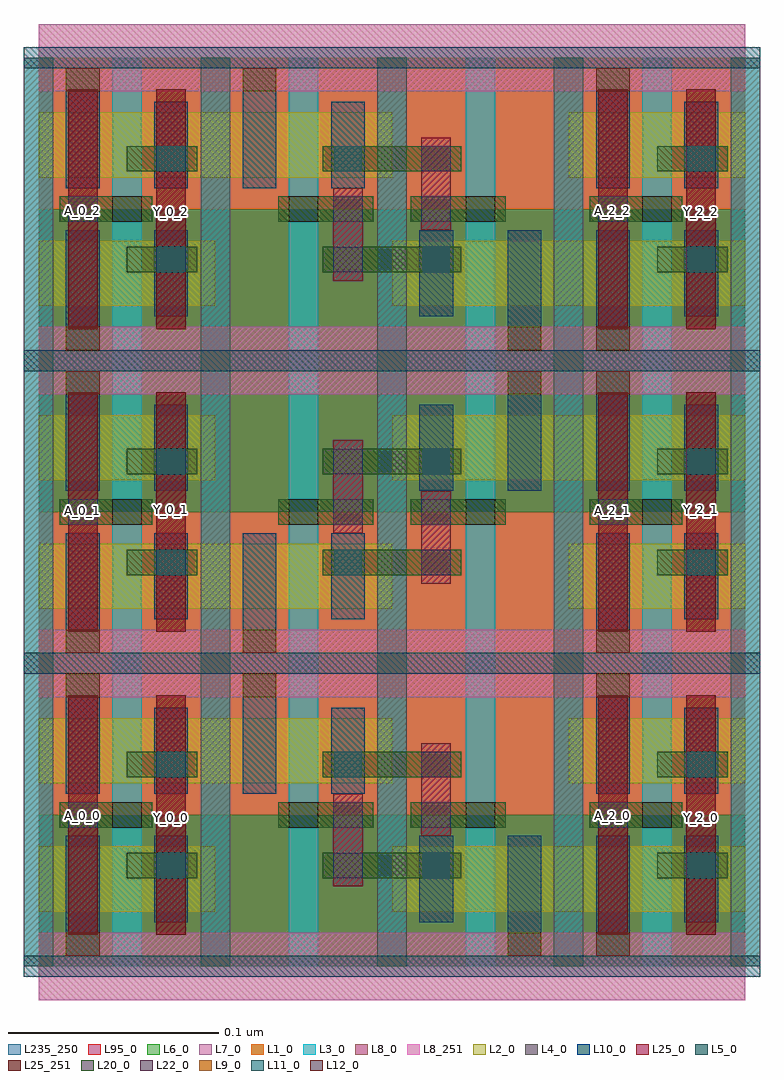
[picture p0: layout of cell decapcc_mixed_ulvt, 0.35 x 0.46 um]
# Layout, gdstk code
from math import pi, radians
import gdstk
lib = gdstk.Library(unit=1e-6, precision=5e-10)
def R(c, l, rs):  # rectangles x0, y0, x1, y1
    for r in rs: c.add(gdstk.rectangle(r[:2], r[2:], *l))
def A(c, l, x, y, w, h, nx, ny, dx, dy):  # array of equal rectangles
    R(c, l, [(x+i*dx, y+j*dy, x+i*dx+w, y+j*dy+h) for i in range(nx) for j in range(ny)])
L1_0 = (1, 0)
L2_0 = (2, 0)
L3_0 = (3, 0)
L4_0 = (4, 0)
L5_0 = (5, 0)
L6_0 = (6, 0)
L7_0 = (7, 0)
L8_0 = (8, 0)
L8_251 = (8, 251)
L9_0 = (9, 0)
L10_0 = (10, 0)
L11_0 = (11, 0)
L12_0 = (12, 0)
L20_0 = (20, 0)
L22_0 = (22, 0)
L25_0 = (25, 0)
L25_251 = (25, 251)
L95_0 = (95, 0)
L235_250 = (235, 250)

gt2_6t_inv_x1_w31_ulvt = lib.new_cell('gt2_6t_inv_x1_w31_ulvt')
R(gt2_6t_inv_x1_w31_ulvt, L1_0, [(0,0.072,0.084,0.144)])
R(gt2_6t_inv_x1_w31_ulvt, L2_0, [(0,0.026,0.084,0.057), (0,0.087,0.084,0.118)])
A(gt2_6t_inv_x1_w31_ulvt, L3_0, -0.007, 0, 0.014, 0.144, 3, 1, 0.042, 0)
R(gt2_6t_inv_x1_w31_ulvt, L4_0, [(-0.007,0,0.007,0.144), (0.077,0,0.091,0.144)])
R(gt2_6t_inv_x1_w31_ulvt, L5_0, [(-0.007,-0.005,0.091,0.005), (-0.007,0.139,0.091,0.149)])
R(gt2_6t_inv_x1_w31_ulvt, L6_0, [(0,0,0.084,0.072)])
R(gt2_6t_inv_x1_w31_ulvt, L7_0, [(0,0.072,0.084,0.144)])
R(gt2_6t_inv_x1_w31_ulvt, L8_0, [(0,-0.016,0.084,0.016), (0,0.128,0.084,0.16)])
R(gt2_6t_inv_x1_w31_ulvt, L8_251, [(0,-0.016,0.084,0.016), (0,0.128,0.084,0.16)])
R(gt2_6t_inv_x1_w31_ulvt, L9_0, [(0.013,0.005,0.029,0.016), (0.013,0.128,0.029,0.139)])
R(gt2_6t_inv_x1_w31_ulvt, L10_0, [(0.013,0.005,0.029,0.062), (0.055,0.021,0.071,0.062), (0.013,0.082,0.029,0.139), (0.055,0.082,0.071,0.123)])
R(gt2_6t_inv_x1_w31_ulvt, L11_0, [(0.0565,0.042,0.0695,0.054), (0.0565,0.09,0.0695,0.102)])
R(gt2_6t_inv_x1_w31_ulvt, L12_0, [(0.035,0.066,0.049,0.078)])
R(gt2_6t_inv_x1_w31_ulvt, L20_0, [(0.042,0.042,0.0755,0.054), (0.01,0.066,0.054,0.078), (0.042,0.09,0.0755,0.102)])
R(gt2_6t_inv_x1_w31_ulvt, L22_0, [(0.056,0.042,0.07,0.054), (0.014,0.066,0.028,0.078), (0.056,0.09,0.07,0.102)])
R(gt2_6t_inv_x1_w31_ulvt, L25_0, [(0.014,0.015,0.028,0.129), (0.056,0.015,0.07,0.129)])
R(gt2_6t_inv_x1_w31_ulvt, L25_251, [(0.014,0.015,0.028,0.129), (0.056,0.015,0.07,0.129)])
R(gt2_6t_inv_x1_w31_ulvt, L95_0, [(0,0,0.084,0.144)])
R(gt2_6t_inv_x1_w31_ulvt, L235_250, [(0,0,0.084,0.144)])
gt2_6t_inv_x1_w31_ulvt.add(gdstk.Label('vdd', (0.022,0.144), layer=8, texttype=251))
gt2_6t_inv_x1_w31_ulvt.add(gdstk.Label('vss', (0.042,0.0035), layer=8, texttype=251))
gt2_6t_inv_x1_w31_ulvt.add(gdstk.Label('A', (0.021,0.0715), layer=25, texttype=251))
gt2_6t_inv_x1_w31_ulvt.add(gdstk.Label('Y', (0.063,0.071), layer=25, texttype=251))

gt2_6t_decapcc_cp_w31_ul = lib.new_cell('gt2_6t_decapcc_cp_w31_ulvt')
R(gt2_6t_decapcc_cp_w31_ul, L1_0, [(0,0.072,0.168,0.144)])
R(gt2_6t_decapcc_cp_w31_ul, L2_0, [(0,0.026,0.084,0.057), (0.084,0.087,0.168,0.118)])
A(gt2_6t_decapcc_cp_w31_ul, L3_0, -0.007, 0, 0.014, 0.144, 5, 1, 0.042, 0)
A(gt2_6t_decapcc_cp_w31_ul, L4_0, -0.007, 0, 0.014, 0.144, 3, 1, 0.084, 0)
R(gt2_6t_decapcc_cp_w31_ul, L5_0, [(-0.007,-0.005,0.175,0.005), (-0.007,0.139,0.175,0.149)])
R(gt2_6t_decapcc_cp_w31_ul, L6_0, [(0,0,0.168,0.072)])
R(gt2_6t_decapcc_cp_w31_ul, L7_0, [(0,0.072,0.168,0.144)])
R(gt2_6t_decapcc_cp_w31_ul, L8_0, [(0,-0.016,0.168,0.016), (0,0.128,0.168,0.16)])
R(gt2_6t_decapcc_cp_w31_ul, L8_251, [(0,-0.016,0.168,0.016), (0,0.128,0.168,0.16)])
R(gt2_6t_decapcc_cp_w31_ul, L9_0, [(0.013,0.005,0.029,0.016), (0.139,0.128,0.155,0.139)])
R(gt2_6t_decapcc_cp_w31_ul, L10_0, [(0.013,0.005,0.029,0.062), (0.055,0.021,0.071,0.062), (0.097,0.082,0.113,0.123), (0.139,0.082,0.155,0.139)])
R(gt2_6t_decapcc_cp_w31_ul, L11_0, [(0.0565,0.042,0.0695,0.054), (0.0985,0.09,0.1115,0.102)])
R(gt2_6t_decapcc_cp_w31_ul, L12_0, [(0.035,0.066,0.049,0.078), (0.119,0.066,0.133,0.078)])
R(gt2_6t_decapcc_cp_w31_ul, L20_0, [(0.051,0.042,0.117,0.054), (0.03,0.066,0.075,0.078), (0.093,0.066,0.138,0.078), (0.051,0.09,0.117,0.102)])
R(gt2_6t_decapcc_cp_w31_ul, L22_0, [(0.098,0.042,0.112,0.054), (0.056,0.066,0.07,0.078), (0.098,0.066,0.112,0.078), (0.056,0.09,0.07,0.102)])
R(gt2_6t_decapcc_cp_w31_ul, L25_0, [(0.098,0.038,0.112,0.082), (0.056,0.062,0.07,0.106)])
R(gt2_6t_decapcc_cp_w31_ul, L95_0, [(0,0,0.168,0.144)])
R(gt2_6t_decapcc_cp_w31_ul, L235_250, [(0,0,0.168,0.144)])
gt2_6t_decapcc_cp_w31_ul.add(gdstk.Label('vss', (0.084,0), layer=8, texttype=251))
gt2_6t_decapcc_cp_w31_ul.add(gdstk.Label('vdd', (0.084,0.144), layer=8, texttype=251))

decapcc_mixed_ulvt = lib.new_cell('decapcc_mixed_ulvt')
decapcc_mixed_ulvt.add(gdstk.Reference(gt2_6t_inv_x1_w31_ulvt, (0,0)))
decapcc_mixed_ulvt.add(gdstk.Reference(gt2_6t_decapcc_cp_w31_ul, (0.252,0), rotation=pi, x_reflection=True))
decapcc_mixed_ulvt.add(gdstk.Reference(gt2_6t_inv_x1_w31_ulvt, (0.252,0)))
decapcc_mixed_ulvt.add(gdstk.Reference(gt2_6t_inv_x1_w31_ulvt, (0,0.288), x_reflection=True))
decapcc_mixed_ulvt.add(gdstk.Reference(gt2_6t_decapcc_cp_w31_ul, (0.252,0.288), rotation=pi))
decapcc_mixed_ulvt.add(gdstk.Reference(gt2_6t_inv_x1_w31_ulvt, (0.252,0.288), x_reflection=True))
decapcc_mixed_ulvt.add(gdstk.Reference(gt2_6t_inv_x1_w31_ulvt, (0,0.288)))
decapcc_mixed_ulvt.add(gdstk.Reference(gt2_6t_decapcc_cp_w31_ul, (0.252,0.288), rotation=pi, x_reflection=True))
decapcc_mixed_ulvt.add(gdstk.Reference(gt2_6t_inv_x1_w31_ulvt, (0.252,0.288)))
decapcc_mixed_ulvt.add(gdstk.Label('A_0_0', (0.021,0.0715), layer=25, texttype=251))
decapcc_mixed_ulvt.add(gdstk.Label('Y_0_0', (0.063,0.071), layer=25, texttype=251))
decapcc_mixed_ulvt.add(gdstk.Label('A_2_0', (0.273,0.0715), layer=25, texttype=251))
decapcc_mixed_ulvt.add(gdstk.Label('Y_2_0', (0.315,0.071), layer=25, texttype=251))
decapcc_mixed_ulvt.add(gdstk.Label('A_0_1', (0.021,0.2165), layer=25, texttype=251))
decapcc_mixed_ulvt.add(gdstk.Label('Y_0_1', (0.063,0.217), layer=25, texttype=251))
decapcc_mixed_ulvt.add(gdstk.Label('A_2_1', (0.273,0.2165), layer=25, texttype=251))
decapcc_mixed_ulvt.add(gdstk.Label('Y_2_1', (0.315,0.217), layer=25, texttype=251))
decapcc_mixed_ulvt.add(gdstk.Label('A_0_2', (0.021,0.3595), layer=25, texttype=251))
decapcc_mixed_ulvt.add(gdstk.Label('Y_0_2', (0.063,0.359), layer=25, texttype=251))
decapcc_mixed_ulvt.add(gdstk.Label('A_2_2', (0.273,0.3595), layer=25, texttype=251))
decapcc_mixed_ulvt.add(gdstk.Label('Y_2_2', (0.315,0.359), layer=25, texttype=251))

lib.write_gds('decapcc_mixed_ulvt.gds')
